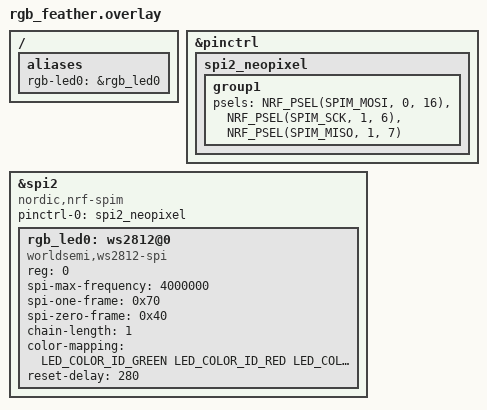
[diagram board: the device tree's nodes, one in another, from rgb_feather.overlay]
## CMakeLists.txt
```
# SPDX-License-Identifier: Apache-2.0

cmake_minimum_required(VERSION 3.20.0)

# ANT+-only Zwift dongle - the headline product: minimum latency and loss,
# built for whichever of the boards in boards/ a user actually has. No BT, no
# Thread, no coexistence instrumentation - that is apps/dongle_thread's job,
# and stripping it out of this image entirely is deliberate, not an
# oversight: every byte and every interrupt priority here exists to answer
# ANT+ traffic as fast as possible, and a second radio stack even linked in
# and idle is one more thing between an interrupt firing and a slot closing.
#
# The sysbuild-cache reader and the RADIANT_BACKEND selection/assertion
# machinery are shared with every other RadiANT app (apps/hrm_ble,
# apps/dongle_thread) rather than copy-pasted - see that file for the
# sysbuild mechanics this depends on. The ANT_RADIO axis (sdk_ant vs core vs
# stub) is the ANT-serial-dongle-specific half of the same idea, and lives in
# apps/common/ instead, for the reason that file's own header gives.
include("${CMAKE_CURRENT_SOURCE_DIR}/../../cmake/radiant_backend.cmake")
include("${CMAKE_CURRENT_SOURCE_DIR}/../common/ant_radio_backend.cmake")

# radiant is appended unconditionally, and the asymmetry with sdk-ant is
# deliberate. sdk-ant is appended only for -DANT_RADIO=sdk_ant because it may
# not be on disk at all; radiant is in this repository and always is. So it
# is always a module and CONFIG_RADIANT gates it, which is both the ordinary
# Zephyr idiom and a better test: an sdk_ant build then asserts
# CONFIG_RADIANT=n positively, rather than proving nothing by the module's
# absence. radiant/CMakeLists.txt returns immediately when the symbol is n,
# so an sdk_ant build cannot reach a <radiant/...> header either.
#
# The HAL backend is resolved unconditionally too, even though it is only
# used when ANT_RADIO=core: resolving it once is simpler than threading it
# through every ANT_RADIO branch, and a stray RADIANT_BACKEND cache entry on
# an sdk_ant/stub build is harmless since nothing reads it - ant_select_radio()
# discards this text outside the core branch, so no CONFIG_RADIANT_BACKEND_*
# line reaches an sdk_ant or stub .config and radiant_assert_backend() is not
# called there either.
#
# THE DEFAULT IS "nrf". It was "null" for a long time on the argument that a
# bare `west build` should always configure; that argument is withdrawn. The
# null backend refuses every arm, and an image built with it enumerates,
# answers every host command with OK, runs every state machine and finds no
# sensors - which reads as a dead antenna, not a build mistake. It has cost
# this project a rationed Feather flash and a whole Zwift session at least
# once, and the flag has been omitted three separate times.
#
# A default that is wrong-but-buildable trades a loud failure for a silent
# one. `nrf` is the backend every real build of this application asks for, so
# the default now agrees with the intent, and a board that cannot support it
# fails at configure time with radiant_assert_backend()'s message rather than
# at a bench an hour later.
radiant_select_backend("${CMAKE_CURRENT_SOURCE_DIR}/../../radiant" "nrf" RADIANT_BACKEND_CONF)
ant_select_radio("${CMAKE_CURRENT_SOURCE_DIR}" "" "${RADIANT_BACKEND_CONF}" ANT_RADIO_CONF)

# Write only on a change. Zephyr adds every merged fragment to
# CMAKE_CONFIGURE_DEPENDS, so rewriting an identical file each configure
# would hand ninja a freshly-stamped dependency of the configure step it just
# ran.
#
# It lands in the application binary directory because Zephyr globs *.conf
# there and merges the result *after* everything else, including
# -DEXTRA_CONF_FILE. That ordering is what makes this authoritative: the
# backend CMake actually compiled and the backend Kconfig records cannot
# disagree.
set(ANT_RADIO_CONF_FILE "${CMAKE_CURRENT_BINARY_DIR}/ant_radio_backend.conf")
set(ANT_RADIO_CONF_EXISTING "")
if(EXISTS "${ANT_RADIO_CONF_FILE}")
  file(READ "${ANT_RADIO_CONF_FILE}" ANT_RADIO_CONF_EXISTING)
endif()
if(NOT ANT_RADIO_CONF_EXISTING STREQUAL ANT_RADIO_CONF)
  file(WRITE "${ANT_RADIO_CONF_FILE}" "# Generated by CMakeLists.txt from -DANT_RADIO. Do not edit; do not commit.\n${ANT_RADIO_CONF}")
endif()

find_package(Zephyr REQUIRED HINTS $ENV{ZEPHYR_BASE})
project(radiant_dongle)

# See apps/common/ant_radio_backend.cmake's ant_assert_radio() - only
# relevant when ANT_RADIO chose radiant in the first place, and it is the
# function's own job to check that, not this call site's.
ant_assert_radio("radiant_dongle")

target_sources(app PRIVATE src/main.c)

# ── apps/common: the antr_* seam, the serial bridge and its transports ─────
#
# One source list, added fresh into this application's own image - see that
# file's own header for why it is include()d rather than add_subdirectory()'d
# (a plain zephyr_library() there does not link). CONFIG_ANT_DONGLE_TRANSPORT_*
# (set by the choice in Kconfig) and
# CONFIG_ANT_DONGLE_RADIO_*/CONFIG_RADIANT_ANTR_API (set above by
# ant_select_radio() and by apps/common/Kconfig.antr_api's default) together
# decide what actually compiles from it into this image.
include("${CMAKE_CURRENT_SOURCE_DIR}/../common/sources.cmake")

# ── The hostless node's identity (compat-C6) ────────────────────────────────
#
# docs/decisions/0009-hostless-node-identity.md. Default off and off in every
# dongle build: a dongle's epoch authority is the PC behind it, over 0xF3, and
# its pairing scalar arrives over 0xF5 - it wants none of this. The symbol and
# the wiring live here so that a node application built from this tree has a
# home for them, and so the storage backend is selected the same way every
# other backend in this project is.
#
# The counters' storage is a seam (radiant/src/node/node_nvm.h) with no
# default implementation, which is why the backend is a separate condition
# rather than being folded into the one above: a build that selects the
# identity and no backend must fail at the link, not fall back to RAM.
#
# radiant/src/node, not apps/common/node: this pair lives inside the module
# directory (radiant reaches no path outside itself, and this pair always
# did), but the decision to compile it belongs to this application, same as
# before the apps/ split - nothing in radiant/CMakeLists.txt reads either
# symbol.
if(CONFIG_RADIANT_NODE_IDENT)
  target_sources(app PRIVATE ../../radiant/src/node/node_ident.c)
  target_include_directories(app PRIVATE ../../radiant/src/node)
endif()
if(CONFIG_RADIANT_NODE_NVM_SETTINGS)
  target_sources(app PRIVATE ../../radiant/src/node/node_nvm_settings.c)
endif()
```

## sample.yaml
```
# Twister metadata for the dongle application.
#
# NOT WIRED INTO EITHER CI LANE. .github/workflows/ci.yml and release.yml both
# drive `west build` directly against the matrices they carry themselves, and
# nothing in this repository runs twister. This file is a correctness-of-record
# description of the buildable configurations, not coverage - do not read a
# scenario here as something that is being checked.
#
# EVERY SCENARIO PASSES ANT_RADIO=core EXPLICITLY. Until the 2026-08-20
# switchover they instead passed CONFIG_ANT_EVALUATION_KEY=y, which is a symbol
# that exists ONLY when sdk-ant's Kconfig has been sourced - so every scenario
# here silently required a private checkout, and none of them could configure
# without one. core is what ships; sdk_ant is the A/B comparison reference and
# is built by hand (see scripts/build_all.ps1 -Backend sdk_ant).
sample:
  description: ANT+ USB Dongle (Zwift-compatible, VID 0x0FCF / PID 0x1009)
  name: ANT+ USB Dongle
tests:
  # The shipping Feather image, and it carries the activity NeoPixel: rgb.conf
  # turns the module on and rgb_feather.overlay declares the LED node plus the
  # `rgb-led0` alias it looks up. Either one alone fails the build on purpose.
  # This pairing is what scripts/build_all.ps1's `release` row builds.
  sample.radiant_dongle.feather_uf2:
    platform_allow: adafruit_feather_nrf52840/nrf52840/uf2
    integration_platforms:
      - adafruit_feather_nrf52840/nrf52840/uf2
    tags: ant usb dongle rgb
    build_only: true
    extra_args:
      - ANT_RADIO=core
      - EXTRA_CONF_FILE=rgb.conf
      - EXTRA_DTC_OVERLAY_FILE=rgb_feather.overlay
  sample.radiant_dongle.nrf52840dongle:
    platform_allow: nrf52840dongle/nrf52840
    integration_platforms:
      - nrf52840dongle/nrf52840
    tags: ant usb dongle
    build_only: true
    extra_args: ANT_RADIO=core
  sample.radiant_dongle.promicro_uf2:
    platform_allow: promicro_nrf52840/nrf52840/uf2
    integration_platforms:
      - promicro_nrf52840/nrf52840/uf2
    tags: ant usb dongle
    build_only: true
    extra_args: ANT_RADIO=core
  # Fallback image for boards with no 32.768 kHz crystal; see synth.conf.
  sample.radiant_dongle.promicro_uf2_synth:
    platform_allow: promicro_nrf52840/nrf52840/uf2
    integration_platforms:
      - promicro_nrf52840/nrf52840/uf2
    tags: ant usb dongle
    build_only: true
    extra_args:
      - ANT_RADIO=core
      - EXTRA_CONF_FILE=synth.conf
  # The new USB device stack on a board that can actually be tested against a
  # host. The nRF54 targets have no legacy stack available, so this is what
  # keeps apps/common/usb_ant_class_next.c honest on hardware that exists. Not
  # a shipping image, and not a second Feather product - the Feather ships one
  # image, the row above.
  sample.radiant_dongle.feather_uf2_usbd:
    platform_allow: adafruit_feather_nrf52840/nrf52840/uf2
    integration_platforms:
      - adafruit_feather_nrf52840/nrf52840/uf2
    tags: ant usb dongle usbd
    build_only: true
    extra_args:
      - ANT_RADIO=core
      - EXTRA_CONF_FILE=next.conf
  # nRF54L15 has no USB device peripheral at all, so this build carries the ANT
  # serial protocol over a UART.
  sample.radiant_dongle.nrf54l15dk:
    platform_allow: nrf54l15dk/nrf54l15/cpuapp
    integration_platforms:
      - nrf54l15dk/nrf54l15/cpuapp
    tags: ant uart nrf54
    build_only: true
    extra_args: ANT_RADIO=core
  # nRF54LM20A: the one nRF54L part with a USB controller, and it is a DWC2,
  # so this is the new stack by necessity rather than by preference.
  sample.radiant_dongle.nrf54lm20dk:
    platform_allow: nrf54lm20dk/nrf54lm20a/cpuapp
    integration_platforms:
      - nrf54lm20dk/nrf54lm20a/cpuapp
    tags: ant usb dongle nrf54 usbd
    build_only: true
    extra_args: ANT_RADIO=core
```

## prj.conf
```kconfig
# Board-specific settings live in boards/<board>.conf - the UF2 output and
# code-partition offset for the Feather, RTT wiring for the nRF5340 DK.

# The ANT stack settings that used to sit here - CONFIG_ANT,
# CONFIG_ANT_EVALUATION_KEY, CONFIG_ANT_TOTAL_CHANNELS_ALLOCATED=8 (which is
# what gives Zwift headroom for HRM + power + cadence + extras) and
# CONFIG_ANT_BURST_QUEUE_SIZE - are now written by CMakeLists.txt into a
# generated fragment, alongside the CONFIG_ANT_DONGLE_RADIO_* symbol naming the
# backend. They name symbols that exist only when sdk-ant's Kconfig has been
# sourced, and it is CMake that decides whether that happens; stating them here
# would make every core or stub build fail on an assignment to an undefined
# symbol. Same reasoning as the legacy USB stack settings in Kconfig.

# Logging via RTT only; USB is reserved for the ANT bridge
CONFIG_LOG=y
CONFIG_LOG_MODE_DEFERRED=y
CONFIG_USE_SEGGER_RTT=y
CONFIG_LOG_BACKEND_RTT=y
CONFIG_LOG_BACKEND_UART=n
# Two separate knobs decide what happens when the RTT up-buffer fills, and on
# this board it is always full: nothing ever drains it, because the Feather has
# no debugger to attach one.
#
# The SEGGER-level one is already Zephyr's default, but the alternative
# (SEGGER_RTT_MODE_BLOCK_IF_FIFO_FULL) spins until a host reads, which here
# would be forever. Stating it removes a way for an SDK default to move.
CONFIG_SEGGER_RTT_MODE_NO_BLOCK_SKIP=y
# The log-backend one defaults to BLOCK, which is not the default we want: a
# skipped write is retried LOG_BACKEND_RTT_RETRY_CNT (4) times with
# LOG_BACKEND_RTT_RETRY_DELAY_MS (5) between, so every message past the first
# 1 KB costs ~20 ms of k_msleep for output that no one will ever read. Deferred
# mode confines that to the log thread; diag.conf switches to
# CONFIG_LOG_MODE_IMMEDIATE, where it is spent in the calling thread instead -
# the ANT event handler and the USB work queue.
CONFIG_LOG_BACKEND_RTT_MODE_DROP=y

# Heap and threads
CONFIG_HEAP_MEM_POOL_SIZE=4096
CONFIG_MAIN_STACK_SIZE=2048
CONFIG_RESET_ON_FATAL_ERROR=y
CONFIG_REBOOT=y

# Transport. The default is CONFIG_ANT_DONGLE_TRANSPORT_USB_LEGACY wherever a
# Nordic USBD peripheral exists, which is every board this has shipped on; the
# nRF54 targets pick a different one from their board .conf because they have
# to. The USB identity (VID/PID/strings) and each stack's own settings live in
# the application Kconfig, because the legacy symbols do not exist in a build
# that is not using the legacy stack.
CONFIG_CONSOLE=n
CONFIG_UART_CONSOLE=n
CONFIG_SHELL=n

# Pin bcdDevice rather than letting Zephyr derive it from the kernel version,
# so the hardware ID stays put across rebuilds. Windows caches its driver
# verdict against VID+PID+bcdDevice and will not reconsider a device it has
# already bound, so a moving value quietly creates a new device node on every
# SDK bump. Not verified against a retail stick - the ANT INF matches
# USB\VID_0FCF&PID_1009 without a REV, so the value is free.
CONFIG_ANT_DONGLE_BCD_DEVICE=0x0100

# Ring buffer for USB RX data
CONFIG_RING_BUFFER=y

# GPIO for onboard LED activity signal
CONFIG_GPIO=y

# The boot reset cause (apps/common/ant_reset_cause.c): logged on every boot,
# feeds the UF2 settle, and becomes the reason byte of the boot STARTUP on UART
# builds. USB builds already had it (the USB serial number pulls it in); UART
# builds - the 54L15 and the 5340 net core - did not, so their settle waited
# blind and a self-reboot there was invisible.
CONFIG_HWINFO=y
```

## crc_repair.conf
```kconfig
# CONFIG_RADIANT_CRC_REPAIR opt-in, for the S3 CRC-repair A/B (dB domain).
#
#   west build ... -- "-DEXTRA_CONF_FILE=crc_repair.conf"
#
# Off by default (radiant/Kconfig): the syndrome table and the per-CRC-failure
# lookup cost something for a gain that has never been measured on air - see
# reviewer item 4 in the production-readiness plan. This fragment is the A/B's
# B leg.
#
# CONFIG_RADIANT_PROFILE_SANITY rides along: it is the third refutation for a
# repaired frame (alongside the control-byte and transmission-type checks in
# radiant_crc_repair.h), and an A/B that enables repair without it cannot tell
# a caught mis-repair from an uncaught one.
CONFIG_RADIANT_CRC_REPAIR=y
CONFIG_RADIANT_PROFILE_SANITY=y

# The read path for the four counters this turns on (radiant_api_stats:
# crc_repaired, crc_unrepairable, crc_repair_refuted, crc_repair_implausible)
# comes with the symbol rather than with this fragment: apps/common/
# ant_radio_radiant.c logs them every 10 s from api_housekeep() and once more
# on channel close, both under #if CONFIG_RADIANT_CRC_REPAIR. On the nRF54L15
# DK they land on COM7, which needs DTR asserted.
#
# That read path is what makes an honest null result possible. The S3 decision
# rule requires crc_repaired to be climbing AT the knee before a difference in
# knees may be credited to repair - without the counters, "repair did nothing"
# and "repair never engaged" are the same two numbers, and only one of them is
# a result.
```

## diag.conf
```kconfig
# Diagnostic overlay: send the log to flash instead of RTT, at DBG level.
#
#   west build ... -- "-DEXTRA_CONF_FILE=diag.conf"
#   (or "-DEXTRA_CONF_FILE=stub.conf;diag.conf" to also drop the radio)
#
# Read the result back after a double-tap of RESET with
#   .\scripts\read_flash_log.ps1
#
# This exists because the board has no debugger: RTT compiles but nothing can
# read it. Not for releases - it costs RAM, flash erase cycles and boot time.
# CONFIG_ANT_DONGLE_FLASH_LOG depends on FLASH rather than selecting it: FLASH
# is reachable from LOG through the coredump backend choice, and selecting it
# makes Kconfig report a dependency loop.
CONFIG_FLASH=y
CONFIG_ANT_DONGLE_FLASH_LOG=y

# NCS compiles its OWN k_sys_fatal_error_handler whenever this is y
# (nrf/lib/fatal_error/CMakeLists.txt guards the source on exactly this
# symbol), and apps/common/diag_flash_log.c defines one too - so leaving it at
# its NCS default made this fragment fail to LINK:
#
#   multiple definition of `k_sys_fatal_error_handler';
#   apps/common/diag_flash_log.c:247: first defined here
#
# Our handler is the whole point of a diag build: it commits the log to flash
# before the CPU stops, which is what makes an early fault visible on a board
# with no debugger. NCS's just reboots. So NCS's is the one that goes.
#
# The consequence is deliberate: with this n, diag_flash_log.c's handler halts
# after flushing instead of rebooting. That is the better behaviour here -
# a cold reboot into the same fault would fault again and re-flush, and this
# fragment's own header warns it costs flash erase cycles. A halted board is
# also what "double-tap RESET and read the log back" expects to find.
CONFIG_RESET_ON_FATAL_ERROR=n

# RTT would just be dead weight without a probe attached.
CONFIG_LOG_BACKEND_RTT=n
CONFIG_USE_SEGGER_RTT=n

# Deferred logging drops whatever is still queued when execution stops, which
# is precisely the interesting case. Immediate mode formats in the caller's
# context, so the last line before a hang is already in the buffer.
CONFIG_LOG_MODE_IMMEDIATE=y

# The failure being chased is inside usb_enable(), and its own DBG output names
# the step that failed - "Failed to fixup USB descriptor", endpoint validation,
# the nrfx driver's attach path.
CONFIG_USB_DEVICE_LOG_LEVEL_DBG=y
CONFIG_USB_DRIVER_LOG_LEVEL_DBG=y

# Immediate mode formats every message on the stack of whichever thread logged
# it, and main() is what drives USB bring-up at DBG level. 2 KB (prj.conf) is
# not enough for that, and the overflow would look like the hang being chased.
CONFIG_MAIN_STACK_SIZE=4096
```

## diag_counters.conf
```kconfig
# SPDX-License-Identifier: Apache-2.0
#
# The 0xF7 diagnostic pages (MESG_RADIANT_DIAG, ADR 0023) on an nRF dongle,
# with the 0xF6 health counters they depend on. NOT diag.conf, which is the
# flash-log overlay.
#
#   west ... -- "-DEXTRA_CONF_FILE=diag_counters.conf"
#
# Read with tools/ant_diag.py --serial <serial>. Check the generated .config:
# CONFIG_ANT_DONGLE_DIAG=y and CONFIG_RADIANT_DIAG_COUNTERS=y.
CONFIG_ANT_DONGLE_HEALTH_COUNTERS=y
CONFIG_ANT_DONGLE_DIAG=y
```

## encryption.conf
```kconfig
# Bridge the single channel encryption writes as well as the reads.
#
#   west ... -- "-DEXTRA_CONF_FILE=encryption.conf"
#
# Not part of any released image. See CONFIG_ANT_DONGLE_ENCRYPTION in Kconfig
# for why the default is off: no host on Windows can send 0x7D/0x7E/0x7F,
# because ANT_DLL.dll exports no encryption call at all, so the only thing
# enabling it can do to a shipping dongle is make a mode reachable that nothing
# asked for - on the same path a fitness app depends on.
#
# It exists so the feature can be built and exercised with
# tools/ant_features.py, and so a default-off path does not quietly stop
# compiling.
CONFIG_ANT_DONGLE_ENCRYPTION=y
```

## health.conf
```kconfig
# Enable the 0xF6 health counters (MESG_RADIANT_HEALTH).
#
#   west build app/apps/dongle -- "-DANT_RADIO=core" "-DRADIANT_BACKEND=nrf" \
#                                 "-DEXTRA_CONF_FILE=health.conf"
#   (or "-DEXTRA_CONF_FILE=next.conf;health.conf" for the USB_NEXT stack)
#
# -DRADIANT_BACKEND=nrf is spelled out because this recipe was copied without
# it once, onto a rationed Feather flash, and produced an image with the inert
# null radio. That is no longer the default, but an explicit flag is still what
# a reader should copy - and the .config read-back below is what proves it.
#
# Off by default - see CONFIG_ANT_DONGLE_HEALTH_COUNTERS's own help in
# apps/common/Kconfig.health and the header comment in radiant/include/radiant/ant_health.h
# for why: the `zero-cost` CI job asserts identical section sizes and symbol
# sets against the merge base, and this symbol puts real counters on the
# common path.
#
# This fragment has a matrix entry in .github/workflows/release.yml (both the
# legacy-USB and USB_NEXT builds) with an `assert_config` read-back, on the
# same reasoning as security.conf next to it: a fragment nobody's CI ever
# builds is a fragment nobody notices breaking.
CONFIG_ANT_DONGLE_HEALTH_COUNTERS=y
```

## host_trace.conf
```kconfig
# Log every ANT serial frame between host and dongle (CONFIG_ANT_DONGLE_HOST_TRACE).
#
# For the nRF5340 DK's application core, the one board here that enumerates on
# its own USB port and prints a console at the same time:
#
#   west build -b nrf5340dk/nrf5340/cpuapp apps/dongle -- -DANT_RADIO=core \
#       -DRADIANT_BACKEND=null "-DEXTRA_CONF_FILE=host_trace.conf"
#
# The app core has no RADIO, so that image answers every command exactly as the
# radiant core does and never hears a packet: it shows what a host asks for and
# what is refused, not whether it then finds sensors. Read the console VCOM with
# DTR asserted.
CONFIG_ANT_DONGLE_HOST_TRACE=y

# The DK's board conf puts the nrfx USB driver at DBG under immediate-mode
# logging, which formats several lines per bulk transfer synchronously at
# 115200 baud - enough to delay replies and change what a host does. The
# enumeration-level USB_DEVICE log stays at DBG; the trace above covers the
# bulk traffic.
CONFIG_USB_DRIVER_LOG_LEVEL_INF=y
```

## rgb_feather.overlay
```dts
/* SPDX-License-Identifier: Apache-2.0 */

/*
 * The Adafruit Feather nRF52840 Express's on-board NeoPixel (P0.16), wired up
 * for CONFIG_ANT_DONGLE_RGB_LED. Applied by the Feather's RELEASE build row,
 * via -DEXTRA_DTC_OVERLAY_FILE=rgb_feather.overlay, in both
 * scripts/build_all.ps1 and .github/workflows/release.yml's build-core matrix.
 * The activity indicator is part of the shipping image.
 *
 * WHY THIS IS STILL NOT IN boards/adafruit_feather_nrf52840_nrf52840_uf2.overlay,
 * NOW THAT IT SHIPS. The reason changed and the answer did not.
 *
 * It used to be that the node must not reach the shipping image at all.
 * CONFIG_WS2812_STRIP_SPI is `default y` gated purely on a ws2812 compatible
 * being enabled in devicetree, so declaring the node in the board overlay pulls
 * the LED driver and the SPI subsystem into EVERY Feather build of this
 * application - and the shipping image was one of those builds.
 *
 * It now ships, so that argument is spent. The one that replaces it: the
 * `zero-cost` CI job builds a plain Feather from HEAD and from the merge base
 * and compares them section by section and symbol by symbol. What it is
 * measuring is what the RGB feature costs when it is OFF - the render thread,
 * the ws2812 driver and the SPI subsystem, none of which apps/dongle_thread
 * has, since Kconfig.rgb_led is not sourced there at all. Put the node in
 * boards/ and there is no longer any build of this board with the feature off,
 * so that job would compare two enabled images and measure nothing.
 *
 * The counting hook is no longer part of what that job measures here: it moved
 * to ant_activity.h and CONFIG_ANT_DONGLE_ACTIVITY_COUNT, which the mono led0
 * heartbeat's activity mode turns on in the default image anyway. Its own
 * ((void)0) else-branch is intact and is what an _ACTIVITY=n build gets.
 *
 * PORTING THIS TO ANOTHER BOARD: copy this file to rgb_<board>.overlay, point
 * the psels at that board's LED pin, and keep the `rgb-led0` alias. The C code
 * looks up nothing else. Then add `conf='rgb.conf'` and
 * `overlay='rgb_<board>.overlay'` to that board's row in
 * scripts/build_all.ps1, the way the Feather's release row does.
 */

#include <zephyr/dt-bindings/led/led.h>

&pinctrl {
	/*
	 * MOSI is the only signal that goes anywhere. SCK and MISO are parked on
	 * P1.06/P1.07, which appear in no node and on no header pin of this
	 * board (checked against feather_connector.dtsi and
	 * adafruit_feather_nrf52840_common.dtsi), so they drive nothing.
	 *
	 * They are parked rather than omitted because nrfx carries a reference-
	 * manual note that SPIM's SCK should always be connected. Omitting the
	 * psels does in fact work - Zephyr sets skip_gpio_cfg/skip_psel_cfg, so
	 * nrfx's pin validation is bypassed and init_sck_pin() tolerates
	 * PIN_NOT_CONNECTED - but parking costs nothing and stays inside what
	 * the hardware documentation asks for.
	 *
	 * DO NOT copy the in-tree Actinius precedent's choice of P0.00 for this.
	 * On this board P0.00/P0.01 are XL1/XL2 and carry the 32.768 kHz crystal
	 * that ANT's channel timing depends on.
	 */
	spi2_neopixel: spi2_neopixel {
		group1 {
			psels = <NRF_PSEL(SPIM_MOSI, 0, 16)>,
				<NRF_PSEL(SPIM_SCK, 1, 6)>,
				<NRF_PSEL(SPIM_MISO, 1, 7)>;
		};
	};
};

/*
 * SPIM2, and the instance choice is constrained from three sides. SPIM0 shares
 * its address and IRQ with i2c0, which this board enables. SPIM1 is the board's
 * header SPI on P0.13/14/15. SPIM3 would work but drags in nrfx's nRF52840
 * anomaly-198 workaround, which rewrites the chip-wide AHB slave arbitration
 * register around every transfer - a global bus-arbitration change wrapped
 * around each LED update is the last thing to put near a radio ISR. SPIM2 has
 * no such workaround.
 */
&spi2 {
	compatible = "nordic,nrf-spim";
	status = "okay";
	pinctrl-0 = <&spi2_neopixel>;
	pinctrl-names = "default";
	#address-cells = <1>;
	#size-cells = <0>;

	rgb_led0: ws2812@0 {
		compatible = "worldsemi,ws2812-spi";
		reg = <0>;

		/*
		 * 4 MHz with these frame patterns is the in-tree nRF precedent
		 * (8 SPI bits per WS2812 bit, so 2 us per bit against the 1.25 us
		 * nominal period). It is slightly long and normally works. If the
		 * pixel shows wrong colours or flickers, raise to 8000000 - the
		 * SPIM2 ceiling - with spi-one-frame 0x7c and spi-zero-frame 0x60.
		 */
		spi-max-frequency = <4000000>;
		spi-one-frame = <0x70>;
		spi-zero-frame = <0x40>;

		chain-length = <1>;
		color-mapping = <LED_COLOR_ID_GREEN
				 LED_COLOR_ID_RED
				 LED_COLOR_ID_BLUE>;
		reset-delay = <280>;
	};
};

/ {
	aliases {
		/* The only name apps/common/ant_rgb_led.c knows. */
		rgb-led0 = &rgb_led0;
	};
};
```

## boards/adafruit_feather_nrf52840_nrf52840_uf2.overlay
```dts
/ {
	chosen {
		/delete-property/ zephyr,console;
		/delete-property/ zephyr,shell-uart;
		/delete-property/ zephyr,uart-mcumgr;
		/delete-property/ zephyr,bt-mon-uart;
		/delete-property/ zephyr,bt-c2h-uart;

		/*
		 * The TIMER radiant's nrf backend owns outright, for
		 * -DRADIANT_BACKEND=nrf. It runs at 1 MHz forever and is what
		 * t_sync is hardware-captured into from RADIO's ADDRESS event,
		 * so it cannot be shared: naming it here rather than in the
		 * source is what makes a second user a devicetree conflict
		 * instead of two drivers reprogramming each other's prescaler.
		 *
		 * TIMER4, and the choice is constrained from both ends. The
		 * backend needs FIVE compare/capture channels - t_sync capture,
		 * RX start, window close, software now-capture, TX start - and
		 * on nRF52 only TIMER3 and TIMER4 have more than four, which is
		 * a compile-time #error in radiant_radio_nrf.c rather than
		 * something to discover on the air. TIMER4 is the one of the
		 * two that nothing else on this board claims.
		 *
		 * Without this property the nrf backend does not COMPILE for
		 * this board - which is how it went unnoticed that the product
		 * board had never had one: every core build for the Feather so
		 * far used the null backend, where no TIMER is wanted.
		 */
		radiant,radio-timer = &timer4;
	};
};

&timer4 {
	status = "okay";
};

&board_cdc_acm_uart {
	status = "disabled";
};

&uart0 {
	status = "disabled";
};
```

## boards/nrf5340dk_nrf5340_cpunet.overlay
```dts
/*
 * nRF5340 DK network core - ANT serial on uart0, and the TIMER the backend owns.
 *
 * uart0 is the only UART on this core (nrf5340_cpunet.dtsi declares one), so
 * unlike the nRF54L15 DK there is no second port to give the console. The
 * board DTS already lists uart0 as zephyr,console; that chosen is left in
 * place and simply not honoured, because the .conf keeps prj.conf's
 * CONSOLE=n/UART_CONSOLE=n. Overriding the chosen would change nothing and
 * would make this file disagree with the board for no reason.
 *
 * The pins (P1.00/P1.01 -> the DK's second VCOM) are already in the board's
 * pinctrl. They belong to the APPLICATION core until it grants them, which is
 * radiant/spike/promisc/appcore's job - see the .conf. A build that skips the
 * companion gets a perfectly working ANT stack whose bytes leave on pins that
 * are still owned by the other core.
 */

/ {
	aliases {
		ant-uart = &uart0;
	};

	chosen {
		/*
		 * The TIMER radiant's nrf backend owns outright. It runs at
		 * 1 MHz forever and is what t_sync is hardware-captured into
		 * from RADIO's ADDRESS event, so it cannot be shared - naming
		 * it here rather than in the source makes a second user a
		 * devicetree conflict instead of two drivers reprogramming
		 * each other's prescaler.
		 *
		 * timer1, not timer0. All three network-core TIMERs carry
		 * cc-num = <8>, well past the five the backend requires, so
		 * the choice is about who else wants one: timer0 is the
		 * conventional Bluetooth-controller timer on this core. BT is
		 * off in this image, so timer0 would work today and would
		 * collide the day anyone builds this beside a controller.
		 * timer2 is left spare.
		 */
		radiant,radio-timer = &timer1;
	};
};

&timer1 {
	status = "okay";
};
```

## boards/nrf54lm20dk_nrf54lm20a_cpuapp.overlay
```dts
/*
 * nRF54LM20A DK - the TIMER radiant's nrf backend needs.
 *
 * This file exists only for that one chosen node. Everything else about this
 * board's dongle build is Kconfig, and lives in the .conf beside this file;
 * the console stays on uart20 as the board's own dts has it, and the ANT byte
 * stream leaves over USB (DWC2), not a second VCOM, so there is no ant-uart
 * alias here as there is on the nRF54L15 DK.
 *
 * BUILD-VERIFIED ONLY - there is no LM20 on this bench. See the .conf for what
 * else about this part is untested.
 */

/ {
	chosen {
		/*
		 * The TIMER radiant's nrf backend owns outright, for
		 * -DRADIANT_BACKEND=nrf. It runs at 1 MHz forever and is what
		 * t_sync is hardware-captured into from RADIO's ADDRESS event,
		 * so it cannot be shared: naming it here rather than in the
		 * source is what makes a second user a devicetree conflict
		 * instead of two drivers reprogramming each other's prescaler.
		 *
		 * Without it the backend does not COMPILE - radiant_radio_nrf.c
		 * #errors on a missing radiant,radio-timer, on one that is
		 * `status = "disabled"`, and on one with fewer than five CC
		 * channels. That #error is why this board had never built with
		 * -Backend core -RadiantBackend nrf: the overlay did not exist
		 * at all. Do not delete this as unused.
		 *
		 * timer20, the same choice as the nRF54L15 DK: same family,
		 * same peripheral map, cc-num = 6 here as there (every nRF54L
		 * TIMER has at least six), and free on this board. Like every
		 * TIMER on this SoC it is `status = "disabled"` by default, and
		 * an unclocked peripheral is not addressable - hence the enable
		 * below.
		 *
		 * The one caveat, carried over from the treadmill overlay for
		 * this board: mpsl.rst lists MPSL as owning TIMER10 and TIMER20
		 * on nRF54L while mpsl_hwres.h reserves only TIMER10. TIMER20
		 * was measured not to collide ON THE L15; that measurement has
		 * not been repeated on this part. If a timeslot build here
		 * misbehaves, suspect this line first - TIMER22 behaved
		 * identically on the L15.
		 */
		radiant,radio-timer = &timer20;
	};
};

&timer20 {
	status = "okay";
};
```

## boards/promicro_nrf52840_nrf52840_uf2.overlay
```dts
/*
 * Same story as the other boards: the devicetree pulls in
 * boards/common/usb/cdc_acm_serial.dtsi, which points every console-ish chosen
 * node at a CDC ACM instance on the one USB device we need for the ANT vendor
 * class. Detach them and disable the node, or the USB stack comes up with two
 * classes and neither behaves. Logging goes over RTT (see prj.conf).
 *
 * uart0 is enabled in the board's dts on pins we do not use.
 */
/ {
	chosen {
		/delete-property/ zephyr,console;
		/delete-property/ zephyr,shell-uart;
		/delete-property/ zephyr,uart-mcumgr;
		/delete-property/ zephyr,bt-mon-uart;
		/delete-property/ zephyr,bt-c2h-uart;

		/*
		 * The TIMER radiant's nrf backend owns outright, for
		 * -DRADIANT_BACKEND=nrf. It runs at 1 MHz forever and is what
		 * t_sync is hardware-captured into from RADIO's ADDRESS event,
		 * so it cannot be shared: naming it here rather than in the
		 * source is what makes a second user a devicetree conflict
		 * instead of two drivers reprogramming each other's prescaler.
		 *
		 * TIMER4, the same one the Feather overlay beside this takes,
		 * and for the same reason from both ends. The backend needs
		 * FIVE compare/capture channels - t_sync capture, RX start,
		 * window close, software now-capture, TX start - and on nRF52
		 * only TIMER3 and TIMER4 have more than four (TIMER0-2 have
		 * four, and are conventionally the SoftDevice's). Both are free
		 * on this board; TIMER4 keeps the two nRF52840 boards
		 * identical. Fewer than five CCs is a compile-time #error in
		 * radiant_radio_nrf.c, not something to discover on the air.
		 *
		 * Without this property the nrf backend does not COMPILE for
		 * this board, which is exactly why it was missing: every core
		 * build here so far used the null backend, where no TIMER is
		 * wanted. Deleting it as unused re-breaks
		 * `build_all.ps1 -Backend core -RadiantBackend nrf`.
		 */
		radiant,radio-timer = &timer4;
	};
};

&timer4 {
	status = "okay";
};

&board_cdc_acm_uart {
	status = "disabled";
};

&uart0 {
	status = "disabled";
};
```

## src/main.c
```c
/* SPDX-License-Identifier: Apache-2.0 */

/*
 * ANT+ USB Dongle — main entry point.
 *
 * The boot sequence itself lives in apps/common/ant_dongle_main.c, shared with
 * apps/dongle_thread; see apps/common/ant_dongle_main.h for why. This
 * application adds nothing to it — it is ANT+-only by design, and the weak
 * ant_dongle_post_radio_init() hook is deliberately left at its default no-op
 * here. The two coexistence loads that used to be #if'd into this file are in
 * apps/dongle_thread, which is the only application that links a second
 * wireless stack.
 */

#include "ant_dongle_main.h"

int main(void)
{
	return ant_dongle_main_run();
}
```
